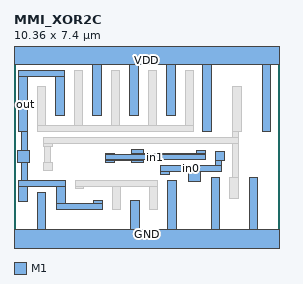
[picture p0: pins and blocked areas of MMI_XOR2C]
MACRO MMI_XOR2C
	CLASS CORE ;
	FOREIGN MMI_XOR2C 0 0 ;
	SIZE 10.36 BY 7.4 ;
	SYMMETRY X Y ;
	SITE CORE1 ;
	PIN out
		DIRECTION output ;
		USE SIGNAL ;
		PORT
			LAYER M1 ;
			RECT 0.18 6.44 1.96 6.67 ;
			LAYER M1 ;
			RECT 0.18 4.295 0.52 6.44 ;
			LAYER M1 ;
			RECT 1.62 4.915 1.96 6.44 ;
			LAYER M1 ;
			RECT 0.29 3.555 0.52 4.295 ;
			LAYER M1 ;
			RECT 0.145 3.105 0.595 3.555 ;
			LAYER M1 ;
			RECT 0.29 2.41 0.52 3.105 ;
			LAYER M1 ;
			RECT 0.18 2.18 2 2.41 ;
			LAYER M1 ;
			RECT 0.18 1.57 0.52 2.18 ;
			LAYER M1 ;
			RECT 1.66 1.495 2 2.18 ;
			LAYER M1 ;
			RECT 3.1 1.495 3.44 1.605 ;
			LAYER M1 ;
			RECT 1.66 1.265 3.44 1.495 ;
		END
		AntennaDiffArea 4.2872 ;
	END out
	PIN in1
		DIRECTION input ;
		USE SIGNAL ;
		PORT
			LAYER M1 ;
			RECT 4.585 3.445 5.035 3.59 ;
			LAYER M1 ;
			RECT 7.11 3.445 7.45 3.555 ;
			LAYER M1 ;
			RECT 3.555 3.39 3.895 3.445 ;
			LAYER M1 ;
			RECT 4.585 3.39 7.45 3.445 ;
			LAYER M1 ;
			RECT 3.555 3.215 7.45 3.39 ;
			LAYER M1 ;
			RECT 3.555 3.16 5.035 3.215 ;
			LAYER M1 ;
			RECT 3.555 3.105 3.895 3.16 ;
			LAYER M1 ;
			RECT 4.585 3.105 5.035 3.16 ;
		END
		AntennaGateArea 2.8152 ;
	END in1
	PIN GND
		DIRECTION inout ;
		USE GROUND ;
		PORT
			LAYER M1 ;
			RECT 0.9 0.5 1.24 1.91 ;
			LAYER M1 ;
			RECT 4.54 0.5 4.88 1.605 ;
			LAYER M1 ;
			RECT 5.98 0.5 6.32 2.41 ;
			LAYER M1 ;
			RECT 7.68 0.5 8.02 2.515 ;
			LAYER M1 ;
			RECT 9.16 0.5 9.5 2.515 ;
			LAYER M1 ;
			RECT 0 -0.5 10.36 0.5 ;
		END
	END GND
	PIN VDD
		DIRECTION inout ;
		USE POWER ;
		PORT
			LAYER M1 ;
			RECT 0 6.9 10.36 7.9 ;
			LAYER M1 ;
			RECT 3.06 4.915 3.4 6.9 ;
			LAYER M1 ;
			RECT 4.5 4.915 4.84 6.9 ;
			LAYER M1 ;
			RECT 5.94 4.915 6.28 6.9 ;
			LAYER M1 ;
			RECT 7.36 4.295 7.7 6.9 ;
			LAYER M1 ;
			RECT 9.66 4.295 10 6.9 ;
		END
	END VDD
	PIN in0
		DIRECTION input ;
		USE SIGNAL ;
		PORT
			LAYER M1 ;
			RECT 7.86 3.185 8.2 3.525 ;
			LAYER M1 ;
			RECT 7.86 2.98 8.09 3.185 ;
			LAYER M1 ;
			RECT 5.7 2.75 8.09 2.98 ;
			LAYER M1 ;
			RECT 5.7 2.64 6.04 2.75 ;
			LAYER M1 ;
			RECT 6.79 2.34 7.255 2.75 ;
		END
		AntennaGateArea 2.8152 ;
	END in0
	OBS
		LAYER M1 ;
		RECT 0.9 4.525 1.24 6.045 ;
		LAYER M1 ;
		RECT 2.34 4.525 2.68 6.67 ;
		LAYER M1 ;
		RECT 3.78 4.525 4.12 6.67 ;
		LAYER M1 ;
		RECT 5.22 4.525 5.56 6.67 ;
		LAYER M1 ;
		RECT 6.66 4.525 7 6.67 ;
		LAYER M1 ;
		RECT 0.9 4.295 7 4.525 ;
		LAYER M1 ;
		RECT 8.51 4.295 8.85 6.055 ;
		LAYER M1 ;
		RECT 8.51 4.055 8.74 4.295 ;
		LAYER M1 ;
		RECT 1.14 3.825 8.74 4.055 ;
		LAYER M1 ;
		RECT 1.14 3.715 1.48 3.825 ;
		LAYER M1 ;
		RECT 1.195 3.11 1.425 3.715 ;
		LAYER M1 ;
		RECT 1.14 2.77 1.48 3.11 ;
		LAYER M1 ;
		RECT 2.38 2.18 5.6 2.41 ;
		LAYER M1 ;
		RECT 2.38 2.065 2.72 2.18 ;
		LAYER M1 ;
		RECT 3.82 1.265 4.16 2.18 ;
		LAYER M1 ;
		RECT 5.26 1.265 5.6 2.18 ;
		LAYER M1 ;
		RECT 8.51 2.515 8.74 3.825 ;
		LAYER M1 ;
		RECT 8.4 1.675 8.74 2.515 ;
	END
END MMI_XOR2C
